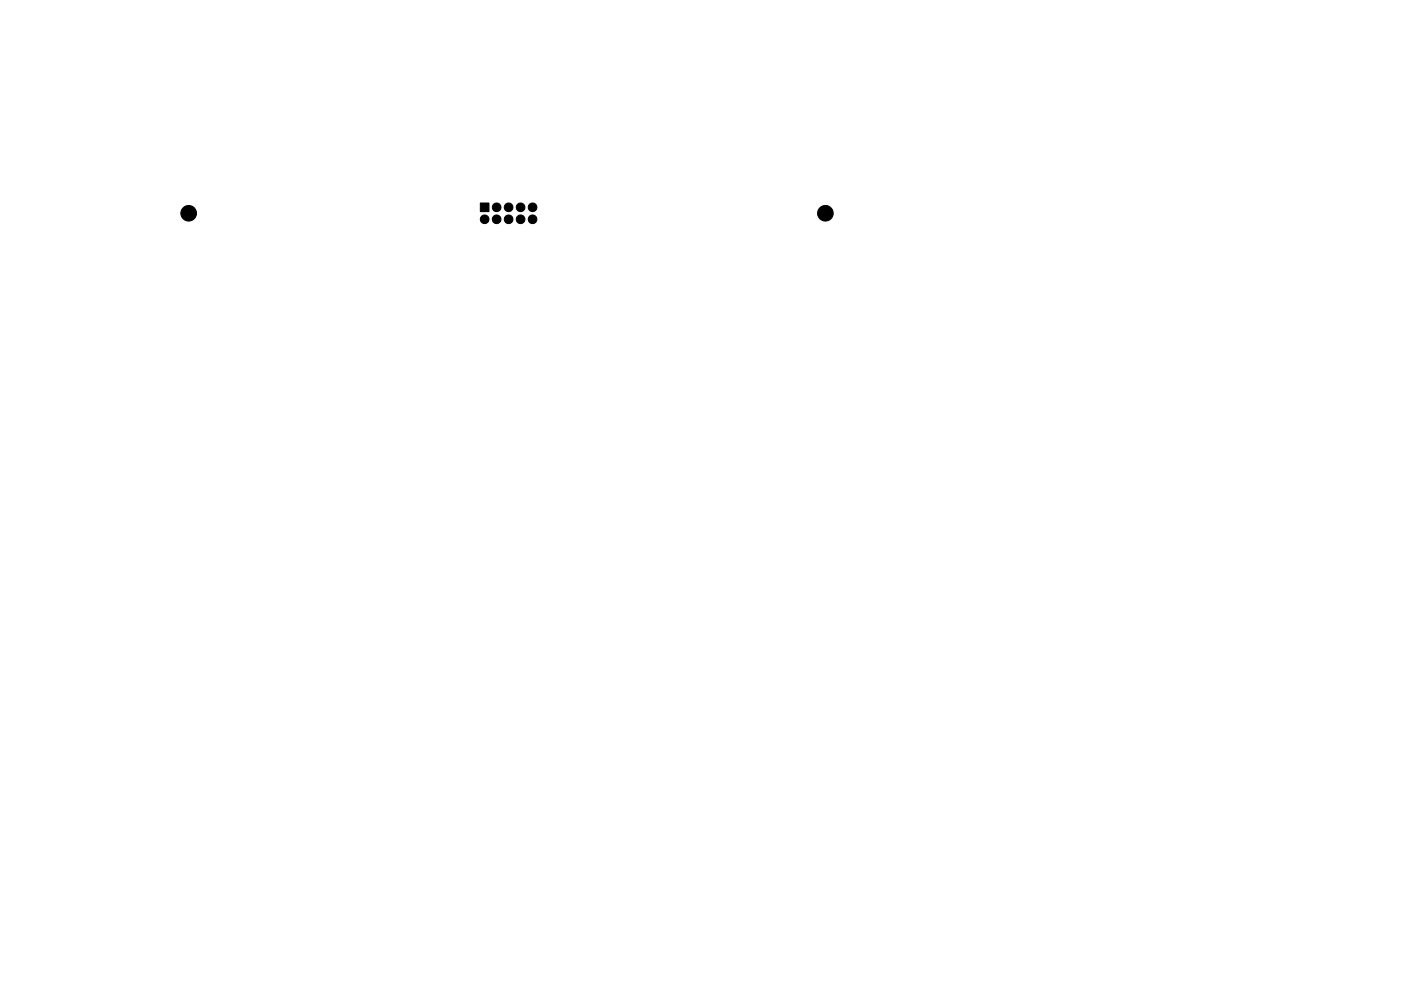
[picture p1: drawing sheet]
<svg xmlns="http://www.w3.org/2000/svg" width="297mm" height="210mm" viewBox="0 0 297 210" stroke-linecap="round" stroke-linejoin="round" font-family="sans-serif">
<g fill="#000" stroke="#000" stroke-width=".21">
<path d="M101.8 43.1h1.9v1.8h-1.9z"/>
<circle cx="40" cy="45.3" r="1.66"/>
<circle cx="102.8" cy="46.5" r=".92"/>
<circle cx="105.3" cy="44" r=".92"/>
<circle cx="105.3" cy="46.5" r=".92"/>
<circle cx="107.8" cy="44" r=".92"/>
<circle cx="107.8" cy="46.5" r=".92"/>
<circle cx="110.4" cy="44" r=".92"/>
<circle cx="110.4" cy="46.5" r=".92"/>
<circle cx="112.9" cy="44" r=".92"/>
<circle cx="112.9" cy="46.5" r=".92"/>
<circle cx="175" cy="45.3" r="1.66"/>
</g>
</svg>
